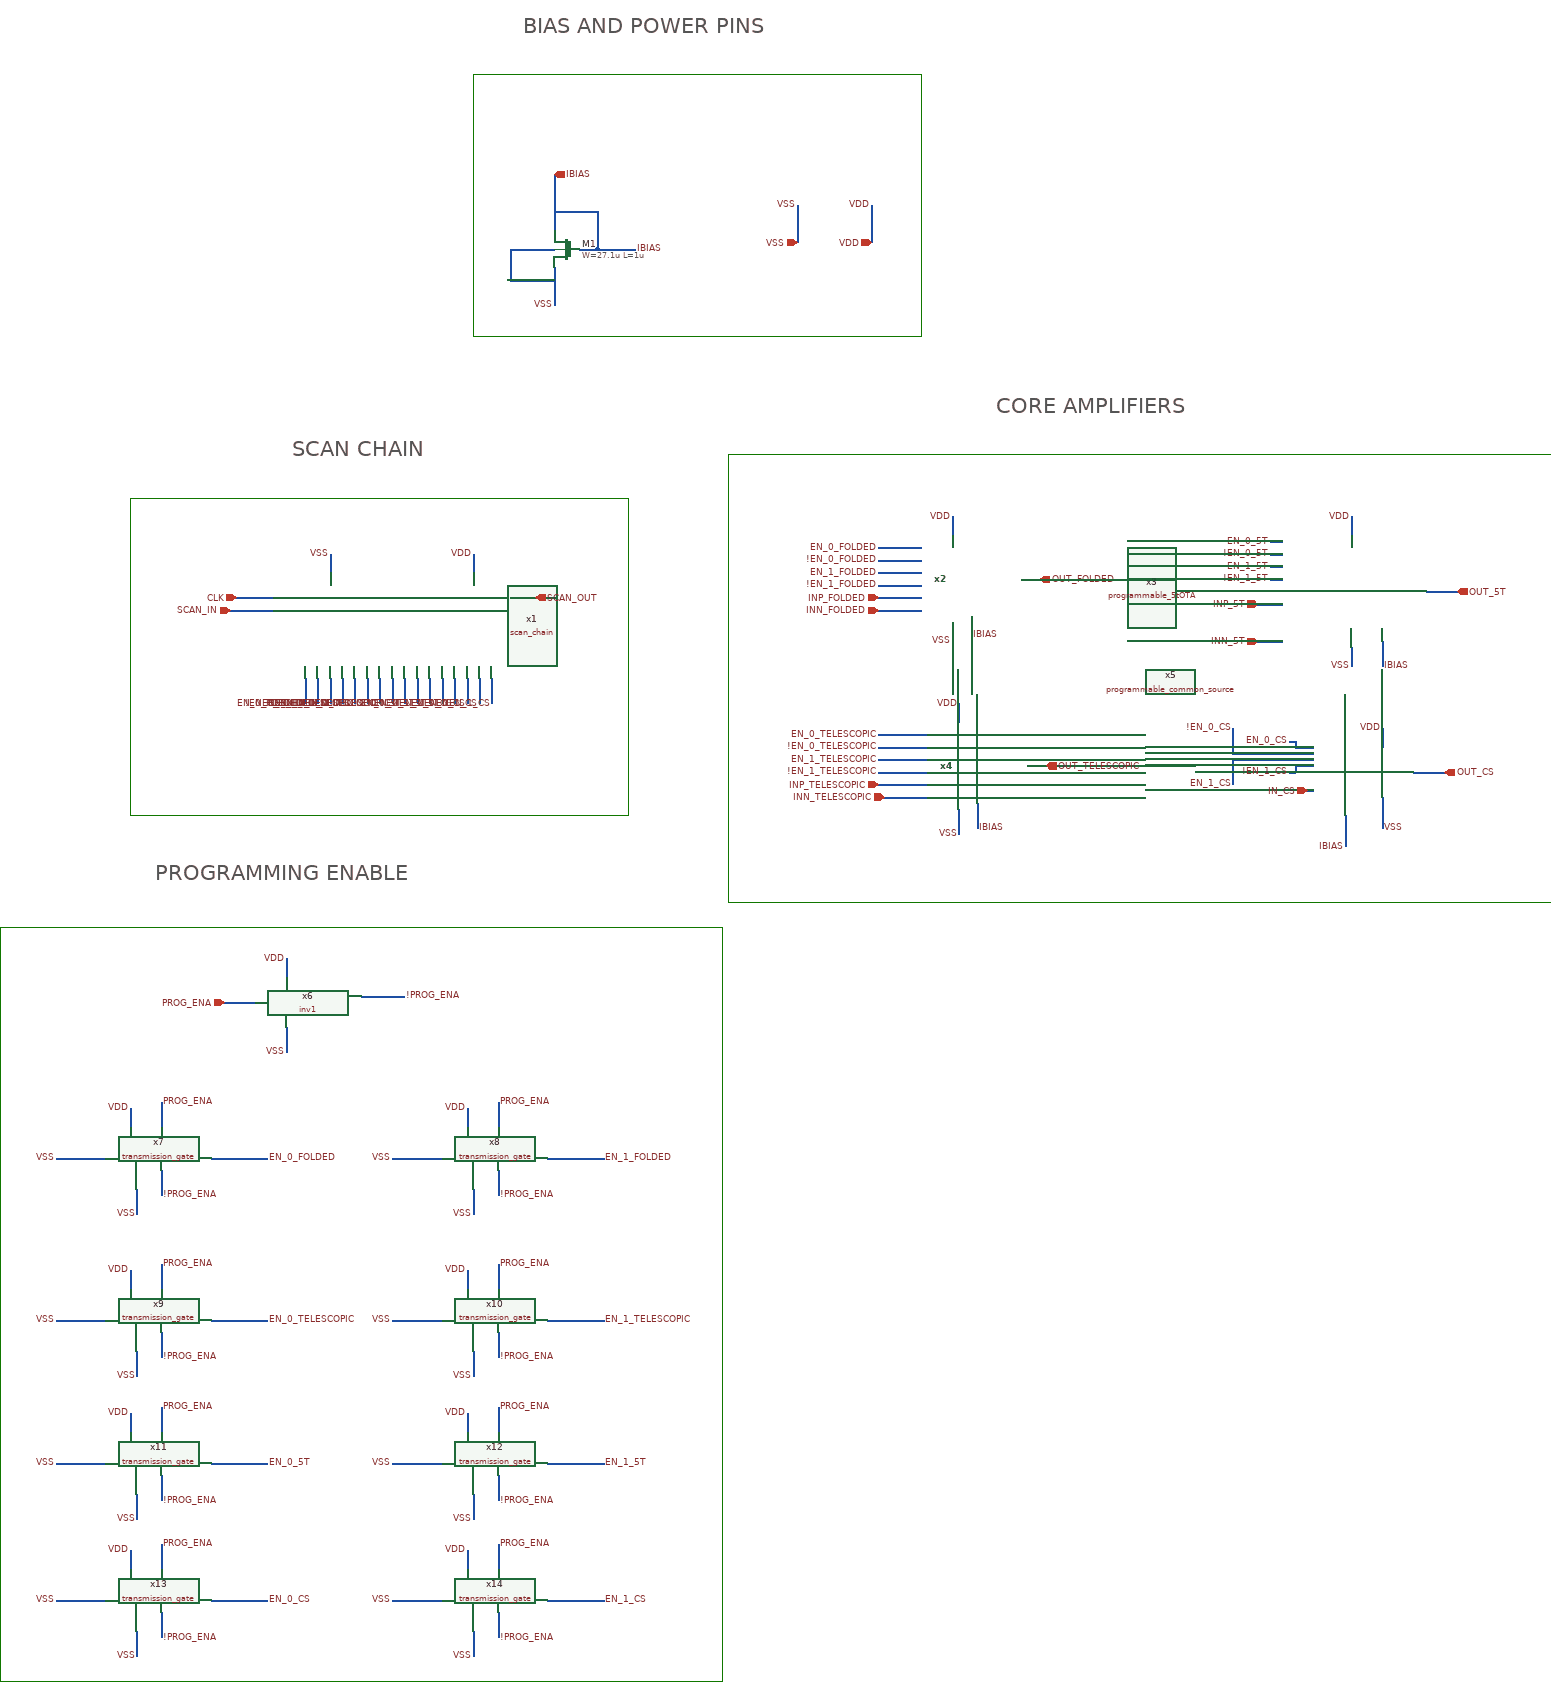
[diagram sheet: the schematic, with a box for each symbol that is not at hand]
v {xschem version=3.4.7 file_version=1.2}
G {}
K {}
V {}
S {}
E {}
L 4 -230 180 -230 690 {}
L 4 -1030 180 -1030 690 {}
L 4 -1030 180 -230 180 {}
L 4 -70 180 -70 830 {}
L 4 -70 830 1260 830 {}
L 4 1260 110 1260 830 {}
L 4 -70 110 1260 110 {}
L 4 -70 110 -70 190 {}
L 4 240 -500 240 -80 {}
L 4 -480 -80 240 -80 {}
L 4 -480 -490 -480 -80 {}
L 4 -480 -500 240 -500 {}
L 4 -480 -500 -480 -490 {}
L 4 -230 180 -230 690 {}
L 4 -1030 180 -1030 690 {}
L 4 -1030 180 -230 180 {}
L 4 -1030 690 -240 690 {}
L 4 -240 690 -230 690 {}
L 4 -80 870 -80 880 {}
L 4 -1240 2080 -80 2080 {}
L 4 -1240 870 -1240 2080 {}
L 4 -1240 870 -80 870 {}
L 4 -80 880 -80 2080 {}
T {PROGRAMMING ENABLE} -990 770 0 0 1 1 {}
T {CORE AMPLIFIERS} 360 20 0 0 1 1 {}
T {BIAS AND POWER PINS} -400 -590 0 0 1 1 {}
T {SCAN CHAIN} -770 90 0 0 1 1 {}
N 400 310 430 310 {lab=OUT_FOLDED}
N 1050 330 1100 330 {lab=OUT_5T}
N 1030 620 1080 620 {lab=OUT_CS}
N 980 550 980 580 {lab=VDD}
N 300 510 300 540 {lab=VDD}
N 290 210 290 240 {lab=VDD}
N 930 210 930 240 {lab=VDD}
N 160 -290 160 -230 {lab=VDD}
N 40 -290 40 -230 {lab=VSS}
N 330 670 330 710 {lab=IBIAS}
N 920 690 920 740 {lab=IBIAS}
N 290 380 290 410 {lab=VSS}
N 930 420 930 450 {lab=VSS}
N 980 660 980 710 {lab=VSS}
N -350 -310 -350 -270 {lab=IBIAS}
N -350 -270 -350 -250 {lab=IBIAS}
N -350 -280 -280 -280 {lab=IBIAS}
N -280 -280 -280 -220 {lab=IBIAS}
N -310 -220 -280 -220 {lab=IBIAS}
N -350 -190 -350 -150 {lab=VSS}
N -420 -220 -350 -220 {lab=VSS}
N -420 -220 -420 -170 {lab=VSS}
N -420 -170 -350 -170 {lab=VSS}
N -350 -150 -350 -130 {lab=VSS}
N -350 -340 -350 -310 {lab=IBIAS}
N -280 -220 -220 -220 {lab=IBIAS}
N 320 370 320 400 {lab=IBIAS}
N 980 410 980 450 {lab=IBIAS}
N 300 680 300 720 {lab=VSS}
N 180 660 250 660 {lab=INN_TELESCOPIC}
N 170 560 250 560 {lab=EN_0_TELESCOPIC}
N 170 360 240 360 {lab=INN_FOLDED}
N 170 340 240 340 {lab=INP_FOLDED}
N 780 410 820 410 {lab=INN_5T}
N 780 350 820 350 {lab=INP_5T}
N -860 340 -800 340 {lab=CLK}
N -420 340 -380 340 {lab=SCAN_OUT}
N -750 470 -750 510 {lab=EN_0_FOLDED}
N -730 470 -730 510 {lab=!EN_0_FOLDED}
N -710 470 -710 510 {lab=EN_1_FOLDED}
N -690 470 -690 510 {lab=!EN_1_FOLDED}
N 170 260 240 260 {lab=EN_0_FOLDED}
N 170 280 240 280 {lab=!EN_0_FOLDED}
N 170 300 240 300 {lab=EN_1_FOLDED}
N 170 320 240 320 {lab=!EN_1_FOLDED}
N 170 580 250 580 {lab=!EN_0_TELESCOPIC}
N 170 600 250 600 {lab=EN_1_TELESCOPIC}
N 170 620 250 620 {lab=!EN_1_TELESCOPIC}
N 170 640 250 640 {lab=INP_TELESCOPIC}
N 800 250 820 250 {lab=EN_0_5T}
N 800 270 820 270 {lab=!EN_0_5T}
N 800 290 820 290 {lab=EN_1_5T}
N 800 310 820 310 {lab=!EN_1_5T}
N 840 580 870 580 {lab=EN_0_CS}
N 840 590 870 590 {lab=!EN_0_CS}
N 840 600 870 600 {lab=EN_1_CS}
N 840 610 870 610 {lab=!EN_1_CS}
N 840 570 840 580 {lab=EN_0_CS}
N 840 610 840 620 {lab=!EN_1_CS}
N 830 620 840 620 {lab=!EN_1_CS}
N 740 600 840 600 {lab=EN_1_CS}
N 740 600 740 640 {lab=EN_1_CS}
N 740 590 840 590 {lab=!EN_0_CS}
N 740 550 740 590 {lab=!EN_0_CS}
N 830 570 840 570 {lab=EN_0_CS}
N -710 270 -710 300 {lab=VSS}
N -480 270 -480 300 {lab=VDD}
N -670 470 -670 510 {lab=EN_0_TELESCOPIC}
N -650 470 -650 510 {lab=!EN_0_TELESCOPIC}
N -630 470 -630 510 {lab=EN_1_TELESCOPIC}
N -610 470 -610 510 {lab=!EN_1_TELESCOPIC}
N -590 470 -590 510 {lab=EN_0_5T}
N -570 470 -570 510 {lab=!EN_0_5T}
N -550 470 -550 510 {lab=EN_1_5T}
N -530 470 -530 510 {lab=!EN_1_5T}
N -510 470 -510 510 {lab=EN_0_CS}
N -490 470 -490 510 {lab=!EN_0_CS}
N -470 470 -470 510 {lab=EN_1_CS}
N -450 470 -450 510 {lab=!EN_1_CS}
N 410 610 440 610 {lab=OUT_TELESCOPIC}
N 860 650 870 650 {lab=IN_CS}
N -870 360 -810 360 {lab=SCAN_IN}
N -810 360 -800 360 {lab=SCAN_IN}
N -880 990 -830 990 {lab=PROG_ENA}
N -660 980 -590 980 {lab=!PROG_ENA}
N -780 1030 -780 1070 {lab=VSS}
N -780 920 -780 950 {lab=VDD}
N -980 1150 -980 1190 {lab=PROG_ENA}
N -980 1260 -980 1300 {lab=!PROG_ENA}
N -1030 1160 -1030 1190 {lab=VDD}
N -1020 1290 -1020 1330 {lab=VSS}
N -900 1240 -810 1240 {lab=EN_0_FOLDED}
N -1150 1240 -1070 1240 {lab=VSS}
N -440 1150 -440 1190 {lab=PROG_ENA}
N -440 1260 -440 1300 {lab=!PROG_ENA}
N -490 1160 -490 1190 {lab=VDD}
N -480 1290 -480 1330 {lab=VSS}
N -360 1240 -270 1240 {lab=EN_1_FOLDED}
N -610 1240 -530 1240 {lab=VSS}
N -980 1410 -980 1450 {lab=PROG_ENA}
N -980 1520 -980 1560 {lab=!PROG_ENA}
N -1030 1420 -1030 1450 {lab=VDD}
N -1020 1550 -1020 1590 {lab=VSS}
N -900 1500 -810 1500 {lab=EN_0_TELESCOPIC}
N -1150 1500 -1070 1500 {lab=VSS}
N -440 1410 -440 1450 {lab=PROG_ENA}
N -440 1520 -440 1560 {lab=!PROG_ENA}
N -490 1420 -490 1450 {lab=VDD}
N -480 1550 -480 1590 {lab=VSS}
N -360 1500 -270 1500 {lab=EN_1_TELESCOPIC}
N -610 1500 -530 1500 {lab=VSS}
N -980 1640 -980 1680 {lab=PROG_ENA}
N -980 1750 -980 1790 {lab=!PROG_ENA}
N -1030 1650 -1030 1680 {lab=VDD}
N -1020 1780 -1020 1820 {lab=VSS}
N -900 1730 -810 1730 {lab=EN_0_5T}
N -1150 1730 -1070 1730 {lab=VSS}
N -440 1640 -440 1680 {lab=PROG_ENA}
N -440 1750 -440 1790 {lab=!PROG_ENA}
N -490 1650 -490 1680 {lab=VDD}
N -480 1780 -480 1820 {lab=VSS}
N -360 1730 -270 1730 {lab=EN_1_5T}
N -610 1730 -530 1730 {lab=VSS}
N -980 1860 -980 1900 {lab=PROG_ENA}
N -980 1970 -980 2010 {lab=!PROG_ENA}
N -1030 1870 -1030 1900 {lab=VDD}
N -1020 2000 -1020 2040 {lab=VSS}
N -900 1950 -810 1950 {lab=EN_0_FOLDED}
N -1150 1950 -1070 1950 {lab=VSS}
N -440 1860 -440 1900 {lab=PROG_ENA}
N -440 1970 -440 2010 {lab=!PROG_ENA}
N -490 1870 -490 1900 {lab=VDD}
N -480 2000 -480 2040 {lab=VSS}
N -360 1950 -270 1950 {lab=EN_1_CS}
N -610 1950 -530 1950 {lab=VSS}
C {libs/core_digital/schem/scan_chain.sym} -610 430 0 0 {name=x1}
C {libs/core_amps/ota_folded_cascode/prgrm_schem/programmable_folded_cascode.sym} 260 310 0 0 {name=x2}
C {libs/core_amps/ota_telescopic/programmable_ota_telescopic schematics/programmable_telescopic_cascode.sym} 270 610 0 0 {name=x4}
C {libs/core_amps/cs_stage/prgrm_schem/programmable_common_source.sym} 890 620 0 0 {name=x5}
C {iopin.sym} 430 310 2 1 {name=p35 lab=OUT_FOLDED}
C {iopin.sym} 1100 330 2 1 {name=p1 lab=OUT_5T}
C {iopin.sym} 440 610 2 1 {name=p2 lab=OUT_TELESCOPIC}
C {iopin.sym} 1080 620 2 1 {name=p3 lab=OUT_CS}
C {lab_pin.sym} 160 -290 0 0 {name=p36 sig_type=std_logic lab=VDD}
C {lab_pin.sym} 40 -290 0 0 {name=p37 sig_type=std_logic lab=VSS}
C {iopin.sym} 40 -230 1 0 {name=p38 lab=VSS}
C {iopin.sym} 160 -230 1 0 {name=p39 lab=VDD}
C {lab_pin.sym} 290 210 0 0 {name=p4 sig_type=std_logic lab=VDD}
C {lab_pin.sym} 930 210 0 0 {name=p5 sig_type=std_logic lab=VDD}
C {lab_pin.sym} 300 510 0 0 {name=p6 sig_type=std_logic lab=VDD}
C {lab_pin.sym} 980 550 0 0 {name=p7 sig_type=std_logic lab=VDD}
C {lab_pin.sym} 290 410 0 0 {name=p8 sig_type=std_logic lab=VSS}
C {lab_pin.sym} 300 720 0 0 {name=p9 sig_type=std_logic lab=VSS}
C {lab_pin.sym} 980 710 0 1 {name=p10 sig_type=std_logic lab=VSS}
C {lab_pin.sym} 930 450 0 0 {name=p11 sig_type=std_logic lab=VSS}
C {symbols/nfet_03v3.sym} -330 -220 0 1 {name=M1
L=1u
W=27.1u
nf=1
m=1
ad="'int((nf+1)/2) * W/nf * 0.18u'"
pd="'2*int((nf+1)/2) * (W/nf + 0.18u)'"
as="'int((nf+2)/2) * W/nf * 0.18u'"
ps="'2*int((nf+2)/2) * (W/nf + 0.18u)'"
nrd="'0.18u / W'" nrs="'0.18u / W'"
sa=0 sb=0 sd=0
model=nfet_03v3
spiceprefix=X
}
C {lab_pin.sym} -220 -220 0 1 {name=p12 sig_type=std_logic lab=IBIAS}
C {lab_pin.sym} 330 710 0 1 {name=p13 sig_type=std_logic lab=IBIAS}
C {iopin.sym} 180 660 2 0 {name=p21 lab=INN_TELESCOPIC}
C {iopin.sym} 170 640 2 0 {name=p22 lab=INP_TELESCOPIC}
C {iopin.sym} 170 340 2 0 {name=p23 lab=INP_FOLDED}
C {iopin.sym} 170 360 2 0 {name=p24 lab=INN_FOLDED}
C {iopin.sym} 860 650 2 0 {name=p25 lab=IN_CS}
C {iopin.sym} 780 410 2 0 {name=p26 lab=INN_5T}
C {iopin.sym} 780 350 2 0 {name=p27 lab=INP_5T}
C {iopin.sym} -860 340 2 0 {name=p28 lab=CLK}
C {iopin.sym} -870 360 2 0 {name=p29 lab=SCAN_IN}
C {iopin.sym} -380 340 2 1 {name=p30 lab=SCAN_OUT}
C {lab_pin.sym} -750 510 3 0 {name=p15 sig_type=std_logic lab=EN_0_FOLDED}
C {lab_pin.sym} 170 260 2 1 {name=p31 sig_type=std_logic lab=EN_0_FOLDED}
C {lab_pin.sym} -730 510 3 0 {name=p32 sig_type=std_logic lab=!EN_0_FOLDED}
C {lab_pin.sym} 170 280 2 1 {name=p33 sig_type=std_logic lab=!EN_0_FOLDED}
C {lab_pin.sym} -710 510 3 0 {name=p34 sig_type=std_logic lab=EN_1_FOLDED}
C {lab_pin.sym} 170 300 0 0 {name=p40 sig_type=std_logic lab=EN_1_FOLDED}
C {lab_pin.sym} -690 510 3 0 {name=p41 sig_type=std_logic lab=!EN_1_FOLDED}
C {lab_pin.sym} 170 320 0 0 {name=p42 sig_type=std_logic lab=!EN_1_FOLDED}
C {lab_pin.sym} 170 560 2 1 {name=p43 sig_type=std_logic lab=EN_0_TELESCOPIC}
C {lab_pin.sym} 170 580 2 1 {name=p44 sig_type=std_logic lab=!EN_0_TELESCOPIC}
C {lab_pin.sym} 170 600 0 0 {name=p45 sig_type=std_logic lab=EN_1_TELESCOPIC}
C {lab_pin.sym} 170 620 0 0 {name=p46 sig_type=std_logic lab=!EN_1_TELESCOPIC}
C {lab_pin.sym} 800 250 2 1 {name=p47 sig_type=std_logic lab=EN_0_5T}
C {lab_pin.sym} 800 270 2 1 {name=p48 sig_type=std_logic lab=!EN_0_5T}
C {lab_pin.sym} 800 290 0 0 {name=p49 sig_type=std_logic lab=EN_1_5T}
C {lab_pin.sym} 800 310 0 0 {name=p50 sig_type=std_logic lab=!EN_1_5T}
C {lab_pin.sym} 830 570 2 1 {name=p51 sig_type=std_logic lab=EN_0_CS}
C {lab_pin.sym} 830 620 0 0 {name=p52 sig_type=std_logic lab=!EN_1_CS}
C {lab_pin.sym} 740 640 0 0 {name=p53 sig_type=std_logic lab=EN_1_CS}
C {lab_pin.sym} 740 550 2 1 {name=p54 sig_type=std_logic lab=!EN_0_CS}
C {lab_pin.sym} -710 270 0 0 {name=p55 sig_type=std_logic lab=VSS}
C {lab_pin.sym} -480 270 0 0 {name=p56 sig_type=std_logic lab=VDD}
C {lab_pin.sym} -670 510 3 0 {name=p57 sig_type=std_logic lab=EN_0_TELESCOPIC}
C {lab_pin.sym} -650 510 3 0 {name=p58 sig_type=std_logic lab=!EN_0_TELESCOPIC}
C {lab_pin.sym} -630 510 3 0 {name=p59 sig_type=std_logic lab=EN_1_TELESCOPIC}
C {lab_pin.sym} -610 510 3 0 {name=p60 sig_type=std_logic lab=!EN_1_TELESCOPIC}
C {lab_pin.sym} -590 510 3 0 {name=p61 sig_type=std_logic lab=EN_0_5T}
C {lab_pin.sym} -570 510 3 0 {name=p62 sig_type=std_logic lab=!EN_0_5T}
C {lab_pin.sym} -550 510 3 0 {name=p63 sig_type=std_logic lab=EN_1_5T}
C {lab_pin.sym} -530 510 3 0 {name=p64 sig_type=std_logic lab=!EN_1_5T}
C {lab_pin.sym} -510 510 3 0 {name=p65 sig_type=std_logic lab=EN_0_CS}
C {lab_pin.sym} -490 510 3 0 {name=p66 sig_type=std_logic lab=!EN_0_CS}
C {lab_pin.sym} -470 510 3 0 {name=p67 sig_type=std_logic lab=EN_1_CS}
C {lab_pin.sym} -450 510 3 0 {name=p68 sig_type=std_logic lab=!EN_1_CS}
C {iopin.sym} -350 -340 1 1 {name=p70 lab=IBIAS}
C {libs/core_amps/ota_5t/prgram_schem/programmable_5tOTA.sym} 970 330 0 0 {name=x3}
C {lab_pin.sym} 920 740 0 0 {name=p20 sig_type=std_logic lab=IBIAS}
C {lab_pin.sym} 980 450 0 1 {name=p19 sig_type=std_logic lab=IBIAS}
C {lab_pin.sym} 320 400 0 1 {name=p17 sig_type=std_logic lab=IBIAS}
C {lab_pin.sym} -350 -130 0 0 {name=p16 sig_type=std_logic lab=VSS}
C {iopin.sym} -880 990 2 0 {name=p14 lab=PROG_ENA}
C {libs/core_digital/schem/inv1.sym} -770 1000 0 0 {name=x6}
C {lab_pin.sym} -780 920 0 0 {name=p18 sig_type=std_logic lab=VDD}
C {lab_pin.sym} -780 1070 0 0 {name=p69 sig_type=std_logic lab=VSS}
C {lab_pin.sym} -590 980 0 1 {name=p71 sig_type=std_logic lab=!PROG_ENA
}
C {libs/core_digital/schem/transmission_gate.sym} -980 1240 0 0 {name=x7}
C {lab_pin.sym} -1030 1160 0 0 {name=p72 sig_type=std_logic lab=VDD}
C {lab_pin.sym} -1020 1330 0 0 {name=p73 sig_type=std_logic lab=VSS}
C {lab_pin.sym} -1150 1240 0 0 {name=p74 sig_type=std_logic lab=VSS}
C {lab_pin.sym} -980 1300 0 1 {name=p75 sig_type=std_logic lab=!PROG_ENA
}
C {lab_pin.sym} -980 1150 0 1 {name=p76 sig_type=std_logic lab=PROG_ENA
}
C {lab_pin.sym} -810 1240 0 1 {name=p77 sig_type=std_logic lab=EN_0_FOLDED
}
C {libs/core_digital/schem/transmission_gate.sym} -440 1240 0 0 {name=x8}
C {lab_pin.sym} -490 1160 0 0 {name=p78 sig_type=std_logic lab=VDD}
C {lab_pin.sym} -480 1330 0 0 {name=p79 sig_type=std_logic lab=VSS}
C {lab_pin.sym} -610 1240 0 0 {name=p80 sig_type=std_logic lab=VSS}
C {lab_pin.sym} -440 1300 0 1 {name=p81 sig_type=std_logic lab=!PROG_ENA
}
C {lab_pin.sym} -440 1150 0 1 {name=p82 sig_type=std_logic lab=PROG_ENA
}
C {lab_pin.sym} -270 1240 0 1 {name=p83 sig_type=std_logic lab=EN_1_FOLDED
}
C {libs/core_digital/schem/transmission_gate.sym} -980 1500 0 0 {name=x9}
C {lab_pin.sym} -1030 1420 0 0 {name=p84 sig_type=std_logic lab=VDD}
C {lab_pin.sym} -1020 1590 0 0 {name=p85 sig_type=std_logic lab=VSS}
C {lab_pin.sym} -1150 1500 0 0 {name=p86 sig_type=std_logic lab=VSS}
C {lab_pin.sym} -980 1560 0 1 {name=p87 sig_type=std_logic lab=!PROG_ENA
}
C {lab_pin.sym} -980 1410 0 1 {name=p88 sig_type=std_logic lab=PROG_ENA
}
C {lab_pin.sym} -810 1500 0 1 {name=p89 sig_type=std_logic lab=EN_0_TELESCOPIC
}
C {libs/core_digital/schem/transmission_gate.sym} -440 1500 0 0 {name=x10}
C {lab_pin.sym} -490 1420 0 0 {name=p90 sig_type=std_logic lab=VDD}
C {lab_pin.sym} -480 1590 0 0 {name=p91 sig_type=std_logic lab=VSS}
C {lab_pin.sym} -610 1500 0 0 {name=p92 sig_type=std_logic lab=VSS}
C {lab_pin.sym} -440 1560 0 1 {name=p93 sig_type=std_logic lab=!PROG_ENA
}
C {lab_pin.sym} -440 1410 0 1 {name=p94 sig_type=std_logic lab=PROG_ENA
}
C {lab_pin.sym} -270 1500 0 1 {name=p95 sig_type=std_logic lab=EN_1_TELESCOPIC
}
C {libs/core_digital/schem/transmission_gate.sym} -980 1730 0 0 {name=x11}
C {lab_pin.sym} -1030 1650 0 0 {name=p96 sig_type=std_logic lab=VDD}
C {lab_pin.sym} -1020 1820 0 0 {name=p97 sig_type=std_logic lab=VSS}
C {lab_pin.sym} -1150 1730 0 0 {name=p98 sig_type=std_logic lab=VSS}
C {lab_pin.sym} -980 1790 0 1 {name=p99 sig_type=std_logic lab=!PROG_ENA
}
C {lab_pin.sym} -980 1640 0 1 {name=p100 sig_type=std_logic lab=PROG_ENA
}
C {lab_pin.sym} -810 1730 0 1 {name=p101 sig_type=std_logic lab=EN_0_5T
}
C {libs/core_digital/schem/transmission_gate.sym} -440 1730 0 0 {name=x12}
C {lab_pin.sym} -490 1650 0 0 {name=p102 sig_type=std_logic lab=VDD}
C {lab_pin.sym} -480 1820 0 0 {name=p103 sig_type=std_logic lab=VSS}
C {lab_pin.sym} -610 1730 0 0 {name=p104 sig_type=std_logic lab=VSS}
C {lab_pin.sym} -440 1790 0 1 {name=p105 sig_type=std_logic lab=!PROG_ENA
}
C {lab_pin.sym} -440 1640 0 1 {name=p106 sig_type=std_logic lab=PROG_ENA
}
C {lab_pin.sym} -270 1730 0 1 {name=p107 sig_type=std_logic lab=EN_1_5T
}
C {libs/core_digital/schem/transmission_gate.sym} -980 1950 0 0 {name=x13}
C {lab_pin.sym} -1030 1870 0 0 {name=p108 sig_type=std_logic lab=VDD}
C {lab_pin.sym} -1020 2040 0 0 {name=p109 sig_type=std_logic lab=VSS}
C {lab_pin.sym} -1150 1950 0 0 {name=p110 sig_type=std_logic lab=VSS}
C {lab_pin.sym} -980 2010 0 1 {name=p111 sig_type=std_logic lab=!PROG_ENA
}
C {lab_pin.sym} -980 1860 0 1 {name=p112 sig_type=std_logic lab=PROG_ENA
}
C {lab_pin.sym} -810 1950 0 1 {name=p113 sig_type=std_logic lab=EN_0_CS
}
C {libs/core_digital/schem/transmission_gate.sym} -440 1950 0 0 {name=x14}
C {lab_pin.sym} -490 1870 0 0 {name=p114 sig_type=std_logic lab=VDD}
C {lab_pin.sym} -480 2040 0 0 {name=p115 sig_type=std_logic lab=VSS}
C {lab_pin.sym} -610 1950 0 0 {name=p116 sig_type=std_logic lab=VSS}
C {lab_pin.sym} -440 2010 0 1 {name=p117 sig_type=std_logic lab=!PROG_ENA
}
C {lab_pin.sym} -440 1860 0 1 {name=p118 sig_type=std_logic lab=PROG_ENA
}
C {lab_pin.sym} -270 1950 0 1 {name=p119 sig_type=std_logic lab=EN_1_CS
}
